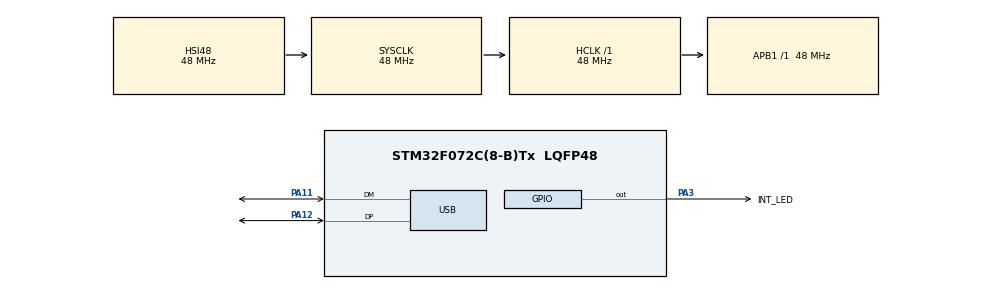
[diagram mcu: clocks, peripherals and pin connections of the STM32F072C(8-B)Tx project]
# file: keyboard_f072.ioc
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Mcu.Family=STM32F0
Mcu.Name=STM32F072C(8-B)Tx
Mcu.Package=LQFP48
NVIC.USB_IRQn=true\:0\:0\:false\:false\:true\:false\:true\:true
PA11.Mode=Device
PA11.Signal=USB_DM
PA12.Mode=Device
PA12.Signal=USB_DP
PA13.Mode=Serial_Wire
PA13.Signal=SYS_SWDIO
PA14.Mode=Serial_Wire
PA14.Signal=SYS_SWCLK
PA3.GPIO_Label=INT_LED
PA3.Signal=GPIO_Output
ProjectManager.HeapSize=0x000
ProjectManager.StackSize=0x400
ProjectManager.TargetToolchain=CMake
RCC.AHBFreq_Value=48000000
RCC.APB1Freq_Value=48000000
RCC.APB1TimFreq_Value=48000000
RCC.HCLKFreq_Value=48000000
RCC.SYSCLKFreq_VALUE=48000000
RCC.SYSCLKSource=RCC_SYSCLKSOURCE_HSI48
USB_DEVICE.CLASS_NAME_FS=CUSTOM_HID
USB_DEVICE.CUSTOM_HID_FS_BINTERVAL=0x10
USB_DEVICE.USBD_CUSTOMHID_OUTREPORT_BUF_SIZE=8
USB_DEVICE.USBD_CUSTOM_HID_REPORT_DESC_SIZE=45
USB_DEVICE.USBD_SELF_POWERED=0
USB_DEVICE.VirtualMode=CustomHid
USB_DEVICE.VirtualModeFS=Custom_Hid_FS
VP_USB_DEVICE_VS_USB_DEVICE_CUSTOM_HID_FS.Mode=CUSTOM_HID_FS
board=custom

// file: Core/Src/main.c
/* USER CODE BEGIN Header */
/**
  ******************************************************************************
  * @file           : main.c
  * @brief          : Main program body
  ******************************************************************************
  * @attention
  *
  * Copyright (c) 2026 STMicroelectronics.
  * All rights reserved.
  *
  * This software is licensed under terms that can be found in the LICENSE file
  * in the root directory of this software component.
  * If no LICENSE file comes with this software, it is provided AS-IS.
  *
  ******************************************************************************
  */
/* USER CODE END Header */
#include "main.h"
#include "usb_device.h"

/* USER CODE BEGIN Includes */
#include "pmain.h"
/* USER CODE END Includes */

void SystemClock_Config(void);
static void MX_GPIO_Init(void);

int main(void)
{

  /* MCU Configuration--------------------------------------------------------*/

  /* Reset of all peripherals, Initializes the Flash interface and the Systick. */
  HAL_Init();

  /* Configure the system clock */
  SystemClock_Config();

  /* Initialize all configured peripherals */
  MX_GPIO_Init();
  MX_USB_DEVICE_Init();
  /* USER CODE BEGIN 2 */

  // project main
  pmain();

  /* USER CODE END 2 */

  /* Infinite loop */
  while (1)
  {

  }
}

void SystemClock_Config(void)
{
  RCC_OscInitTypeDef RCC_OscInitStruct = {0};
  RCC_ClkInitTypeDef RCC_ClkInitStruct = {0};
  RCC_PeriphCLKInitTypeDef PeriphClkInit = {0};

  /** Initializes the RCC Oscillators according to the specified parameters
  * in the RCC_OscInitTypeDef structure.
  */
  RCC_OscInitStruct.OscillatorType = RCC_OSCILLATORTYPE_HSI48;
  RCC_OscInitStruct.HSI48State = RCC_HSI48_ON;
  RCC_OscInitStruct.PLL.PLLState = RCC_PLL_NONE;
  if (HAL_RCC_OscConfig(&RCC_OscInitStruct) != HAL_OK)
  {
    Error_Handler();
  }

  /** Initializes the CPU, AHB and APB buses clocks
  */
  RCC_ClkInitStruct.ClockType = RCC_CLOCKTYPE_HCLK|RCC_CLOCKTYPE_SYSCLK
                              |RCC_CLOCKTYPE_PCLK1;
  RCC_ClkInitStruct.SYSCLKSource = RCC_SYSCLKSOURCE_HSI48;
  RCC_ClkInitStruct.AHBCLKDivider = RCC_SYSCLK_DIV1;
  RCC_ClkInitStruct.APB1CLKDivider = RCC_HCLK_DIV1;

  if (HAL_RCC_ClockConfig(&RCC_ClkInitStruct, FLASH_LATENCY_1) != HAL_OK)
  {
    Error_Handler();
  }
  PeriphClkInit.PeriphClockSelection = RCC_PERIPHCLK_USB;
  PeriphClkInit.UsbClockSelection = RCC_USBCLKSOURCE_HSI48;

  if (HAL_RCCEx_PeriphCLKConfig(&PeriphClkInit) != HAL_OK)
  {
    Error_Handler();
  }
}

static void MX_GPIO_Init(void)
{
  GPIO_InitTypeDef GPIO_InitStruct = {0};

  /* GPIO Ports Clock Enable */
  __HAL_RCC_GPIOC_CLK_ENABLE();
  __HAL_RCC_GPIOF_CLK_ENABLE();
  __HAL_RCC_GPIOA_CLK_ENABLE();
  __HAL_RCC_GPIOB_CLK_ENABLE();

  /*Configure GPIO pin Output Level */
  HAL_GPIO_WritePin(GPIOA, INT_LED_Pin|SWITCH_LED_Pin|GPIO_PIN_5|GPIO_PIN_6
                          |GPIO_PIN_7|GPIO_PIN_15, GPIO_PIN_RESET);

  /*Configure GPIO pin Output Level */
  HAL_GPIO_WritePin(GPIOB, GPIO_PIN_3|GPIO_PIN_4|GPIO_PIN_5|GPIO_PIN_9, GPIO_PIN_RESET);

  /*Configure GPIO pins : PC13 PC14 PC15 */
  GPIO_InitStruct.Pin = GPIO_PIN_13|GPIO_PIN_14|GPIO_PIN_15;
  GPIO_InitStruct.Mode = GPIO_MODE_ANALOG;
  GPIO_InitStruct.Pull = GPIO_NOPULL;
  HAL_GPIO_Init(GPIOC, &GPIO_InitStruct);

  /*Configure GPIO pins : PF0 PF1 */
  GPIO_InitStruct.Pin = GPIO_PIN_0|GPIO_PIN_1;
  GPIO_InitStruct.Mode = GPIO_MODE_ANALOG;
  GPIO_InitStruct.Pull = GPIO_NOPULL;
  HAL_GPIO_Init(GPIOF, &GPIO_InitStruct);

  /*Configure GPIO pins : PA0 PA1 PA2 PA8
                           PA9 PA10 */
  GPIO_InitStruct.Pin = GPIO_PIN_0|GPIO_PIN_1|GPIO_PIN_2|GPIO_PIN_8
                          |GPIO_PIN_9|GPIO_PIN_10;
  GPIO_InitStruct.Mode = GPIO_MODE_ANALOG;
  GPIO_InitStruct.Pull = GPIO_NOPULL;
  HAL_GPIO_Init(GPIOA, &GPIO_InitStruct);

  /*Configure GPIO pins : INT_LED_Pin SWITCH_LED_Pin PA5 PA6
                           PA7 PA15 */
  GPIO_InitStruct.Pin = INT_LED_Pin|SWITCH_LED_Pin|GPIO_PIN_5|GPIO_PIN_6
                          |GPIO_PIN_7|GPIO_PIN_15;
  GPIO_InitStruct.Mode = GPIO_MODE_OUTPUT_PP;
  GPIO_InitStruct.Pull = GPIO_NOPULL;
  GPIO_InitStruct.Speed = GPIO_SPEED_FREQ_LOW;
  HAL_GPIO_Init(GPIOA, &GPIO_InitStruct);

  /*Configure GPIO pins : PB0 PB1 THUMB_L_DETECT_Pin THUMB_B1_Pin
                           THUMB_B2_Pin PB6 PB7 PB8 */
  GPIO_InitStruct.Pin = GPIO_PIN_0|GPIO_PIN_1|THUMB_L_DETECT_Pin|THUMB_B1_Pin
                          |THUMB_B2_Pin|GPIO_PIN_6|GPIO_PIN_7|GPIO_PIN_8;
  GPIO_InitStruct.Mode = GPIO_MODE_INPUT;
  GPIO_InitStruct.Pull = GPIO_NOPULL;
  HAL_GPIO_Init(GPIOB, &GPIO_InitStruct);

  /*Configure GPIO pins : PB12 PB13 PB14 PB15 */
  GPIO_InitStruct.Pin = GPIO_PIN_12|GPIO_PIN_13|GPIO_PIN_14|GPIO_PIN_15;
  GPIO_InitStruct.Mode = GPIO_MODE_ANALOG;
  GPIO_InitStruct.Pull = GPIO_NOPULL;
  HAL_GPIO_Init(GPIOB, &GPIO_InitStruct);

  /*Configure GPIO pins : PB3 PB4 PB5 PB9 */
  GPIO_InitStruct.Pin = GPIO_PIN_3|GPIO_PIN_4|GPIO_PIN_5|GPIO_PIN_9;
  GPIO_InitStruct.Mode = GPIO_MODE_OUTPUT_PP;
  GPIO_InitStruct.Pull = GPIO_NOPULL;
  GPIO_InitStruct.Speed = GPIO_SPEED_FREQ_LOW;
  HAL_GPIO_Init(GPIOB, &GPIO_InitStruct);

}

void Error_Handler(void)
{
  __disable_irq();
  while (1)
  {
  }
}
